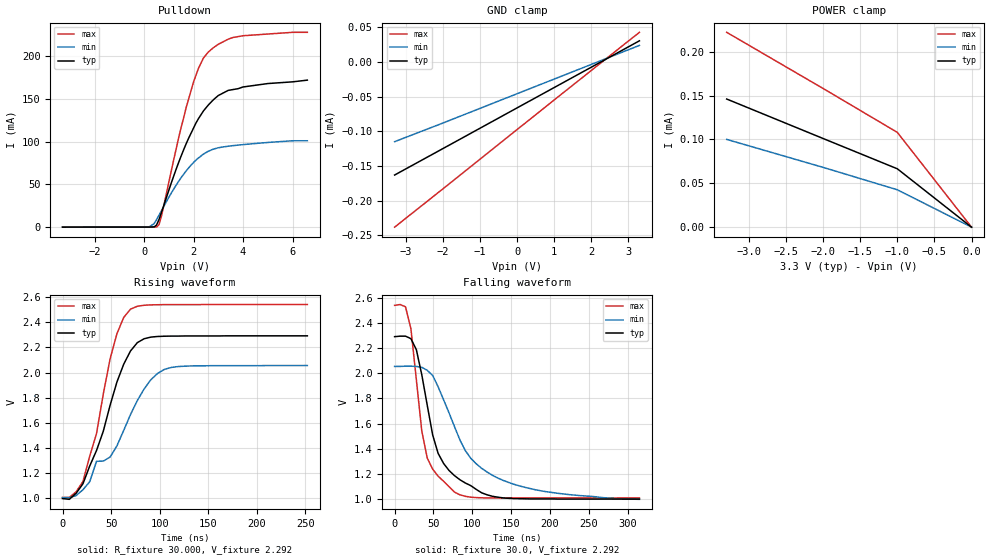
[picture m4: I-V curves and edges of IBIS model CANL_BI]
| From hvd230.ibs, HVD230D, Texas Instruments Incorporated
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[Model]   CANL_BI
Model_type   I/O_open_drain
| Signals   CANH
Vinh = 0.9V
Vinl = 0.5V
Rref = 30   |Note: 60 Ohm differential load;
Vref = 2.3   |tr, tf measured in single ended configuration
| variable   typ   min   max
C_comp   30.0pF   24.0pF   36.0pF
|   typ   min   max
[Temperature Range]   25.0   -40   85
[Voltage range]   3.3V   3.0V   3.6V
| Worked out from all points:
|   slope of the pulldown table from 0 to 0.495 V, typ, clamps not added: 228 ohm
|   rising waveform, R_fixture 30.000, V_fixture 2.292: 20-80 % time 33.4ns typ, 50.6ns min, 26.1ns max; typ from 0.999 V to 2.29 V
|   falling waveform, R_fixture 30.0, V_fixture 2.292: 20-80 % time 32.8ns typ, 61.1ns min, 19.8ns max; typ from 2.29 V to 0.999 V
[Pulldown]
|   Voltage   I(typ)   I(min)   I(max)
-3.3V     -165uA     -149uA     -186uA
200mV     -62uA      33.4uA     -75uA
500mV     2.21mA     8.47mA     -6.56uA
600mV     8.65mA     13.7mA     2.61mA
700mV     16.9mA     19mA       12.7mA
1.4V      75.9mA     53.7mA     105mA
1.7V      97.5mA     65.7mA     140mA
2V        116mA      75.6mA     170mA
2.4V      136mA      85.4mA     198mA
3V        154mA      92.8mA     214mA
3.4V      160mA      94.6mA     220mA
6.6V      172mA      101mA      228mA
[Power_clamp]
| Note that the[POWER_clamp]voltage table is referenced to Vcc
| and is calculated using Vtable=Vcc - Vmeasured.
|   Voltage   I(typ)   I(min)   I(max)
-3.3V     146uA      100uA      222uA
-2V       101uA      68.1uA     158uA
-1V       66.5uA     42.6uA     108uA
0V        0A         0A         0A
[GND_clamp]
|   Voltage   I(typ)   I(min)   I(max)
-3.3V     -163uA     -115uA     -238uA
-2V       -125uA     -88.2uA    -183uA
0V        -66.4uA    -46uA      -97.6uA
1.5V      -22.5uA    -14.4uA    -33.8uA
3.3V      30.2uA     23.6uA     42.4uA
[Ramp]
|   typ   min   max
dV/dt_r   0.776/34ns   0.637/54ns   0.920/25ns
dV/dt_f   0.776/32ns   0.637/60ns   0.920/18ns
R_load = 30ohm  | Note: The measurement is single-ended with 30ohm
|   to Vfixture
[Rising Waveform]
R_fixture = 30.000
V_fixture = 2.292
V_fixture_min = 2.055
V_fixture_max = 2.541
C_fixture = 0.000
L_fixture = 0.000
|  time   V(typ)   V(min)   V(max)
0s        999mV      1.006V     1.008V
21ns      1.116V     1.069V     1.134V
28ns      1.258V     1.133V     1.336V
35ns      1.381V     1.295V     1.516V
49ns      1.741V     1.329V     2.11V
56ns      1.925V     1.418V     2.309V
70ns      2.172V     1.667V     2.504V
91ns      2.282V     1.944V     2.538V
112ns     2.29V      2.041V     2.54V
252ns     2.292V     2.056V     2.541V
[Falling Waveform]
R_fixture = 30.0
V_fixture = 2.292
V_fixture_min = 2.055
V_fixture_max = 2.541
C_fixture = 0p
L_fixture = 0n
|   V(typ)   V(min)   V(max)
0s        2.292V     2.055V     2.541V
14ns      2.296V     2.057V     2.53V
21ns      2.276V     2.057V     2.355V
35ns      1.988V     2.048V     1.54V
42ns      1.746V     2.024V     1.326V
56ns      1.363V     1.893V     1.181V
77ns      1.186V     1.577V     1.055V
98ns      1.106V     1.324V     1.014V
140ns     1.008V     1.147V     1.008V
315ns     999mV      997mV      1.008V
